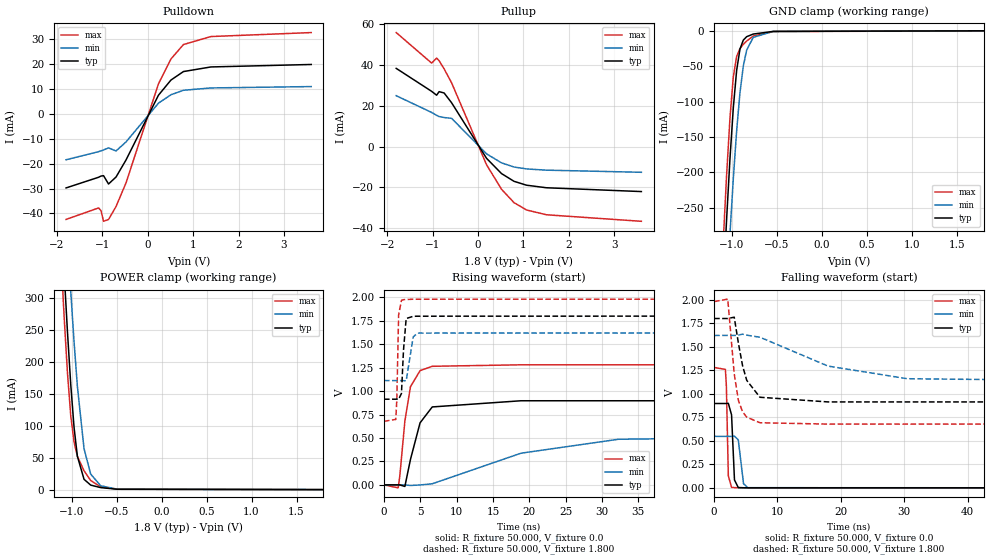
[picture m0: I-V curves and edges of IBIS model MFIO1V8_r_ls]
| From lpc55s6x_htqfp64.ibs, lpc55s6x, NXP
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|   Model MFIO1V8_r_ls
[Model] MFIO1V8_r_ls
Model_type I/O
Polarity   Non-Inverting
Enable   Active-Low
Vinl =  0.540V
Vinh =  1.260V
Vmeas =  0.900V
Cref =  0.0F
Rref =  100.000
Vref =  0.0V
C_comp   2.019pF   1.989pF   2.027pF
C_comp_pullup   1.198pF   1.161pF   1.230pF
C_comp_pulldown   0.670pF   0.640pF   0.684pF
[Model Spec]
Vinh   1.260V   1.134V   1.386V
Vinl   0.540V   0.486V   0.594V
Vmeas   0.900V   0.810V   0.990V
Vref   0.0V   0.0V   0.0V
Cref   0.0F   0.0F   0.0F
Rref   100.000   100.000   100.000
[Temperature Range]   25.000   0.125k   -40.000
[Voltage Range]   1.800V   1.620V   1.980V
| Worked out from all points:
|   slope of the pulldown table from 0 to 0.27 V, typ, clamps not added: 32.2 ohm
|   slope of the pullup table from 0 to 0.27 V, typ, clamps not added: 34.3 ohm
|   GND clamp passes 1 mA (typ) near -0.56 V on its own axis
|   POWER clamp passes 1 mA (typ) near -0.54 V on its own axis
|   rising waveform, R_fixture 50.000, V_fixture 0.0: 20-80 % time 1.89ns typ, 15.8ns min, 1.22ns max; typ from 0 V to 0.897 V
|   rising waveform, R_fixture 50.000, V_fixture 1.800: 20-80 % time 275ps typ, 401ps min, 192ps max; typ from 0.913 V to 1.8 V
|   falling waveform, R_fixture 50.000, V_fixture 0.0: 20-80 % time 312ps typ, 491ps min, 221ps max; typ from 0.897 V to 0 V
|   falling waveform, R_fixture 50.000, V_fixture 1.800: 20-80 % time 1.84ns typ, 13.6ns min, 1.28ns max; typ from 1.8 V to 0.913 V
[Pulldown]
|Voltage   I(typ)   I(min)   I(max)
-1.8V     -29.75mA   -18.45mA   -42.39mA
-1.085V   -25.48mA   -15.2mA    -37.79mA
-1.03V    -24.99mA   -14.87mA   -38.88mA
-975mV    -24.83mA   -14.51mA   -43.15mA
-865mV    -28.18mA   -13.68mA   -42.43mA
-700mV    -25.38mA   -14.92mA   -37.23mA
-480mV    -18.54mA   -11.29mA   -27.73mA
235mV     7.474mA    4.265mA    12.03mA
510mV     13.55mA    7.648mA    22.01mA
785mV     16.96mA    9.446mA    27.8mA
1.39V     18.81mA    10.38mA    31.01mA
3.6V      19.8mA     10.93mA    32.61mA
[Pullup]
|Voltage   I(typ)   I(min)   I(max)
-1.8V     38.29mA    24.9mA     55.82mA
-1.02V    27.05mA    16.71mA    40.87mA
-910mV    25.14mA    15.31mA    43.32mA
-855mV    26.89mA    14.69mA    42.04mA
-745mV    26.24mA    14.22mA    38.06mA
-580mV    21.45mA    13.82mA    31.22mA
190mV     -5.761mA   -3.564mA   -8.914mA
520mV     -13.24mA   -7.997mA   -20.92mA
795mV     -17.02mA   -10.03mA   -27.47mA
1.07V     -18.92mA   -10.95mA   -31.04mA
1.51V     -20.18mA   -11.56mA   -33.41mA
3.6V      -22.04mA   -12.6mA    -36.6mA
[GND_clamp]
|Voltage   I(typ)   I(min)   I(max)
-1.8V     -2.463A    -2.494A    -2.446A
-1.097V   -357.7mA   -460.7mA   -294.8mA
-1.06V    -264.9mA   -370.9mA   -202.5mA
-1.023V   -180.4mA   -286.3mA   -122.9mA
-986mV    -108.7mA   -208.9mA   -65.05mA
-949mV    -56.06mA   -141.4mA   -36.24mA
-912mV    -25.87mA   -87.65mA   -25.01mA
-875mV    -13.21mA   -49.99mA   -19.06mA
-838mV    -8.315mA   -27.44mA   -14.52mA
-764mV    -4.558mA   -9.219mA   -7.395mA
-542mV    -813.9uA   -810.7uA   -1.086mA
1.8V      0A         0A         -4.189uA
[POWER_clamp]
|Voltage   I(typ)   I(min)   I(max)
-1.8V     2.577A     2.626A     2.553A
-1.123V   442.8mA    582.7mA    371.7mA
-1.086V   342mA      487.8mA    272.2mA
-1.049V   248.2mA    396.7mA    184.1mA
-1.012V   164.7mA    310.5mA    115.9mA
-975mV    97.36mA    231.1mA    74.42mA
-938mV    52.18mA    161.5mA    52.15mA
-864mV    16.11mA    64.03mA    29.39mA
-790mV    7.037mA    24.23mA    14.18mA
-679mV    3.116mA    6.059mA    4.361mA
-494mV    554.4uA    627.7uA    712.3uA
1.8V      0A         0A         4.198uA
[Ramp]
| variable   typ   min   max
dV/dt_r   0.538/1.890n   0.328/15.774n   0.768/1.212n
dV/dt_f   0.532/1.835n   0.305/13.605n   0.781/1.279n
R_load = 50.000
[Rising Waveform]
R_fixture= 50.000
V_fixture= 0.0
V_fixture_min= 0.0
V_fixture_max= 0.0
|time   V(typ)   V(min)   V(max)
0s        6.721nV    117.6nV    4.416nV
1.96ns    159.3uV    57.69nV    -31.68mV
2.19ns    -130.7uV   -10.85uV   100.6mV
2.88ns    -16.7mV    114.5uV    679.8mV
3.65ns    271.3mV    -6.131mV   1.047V
4.97ns    661.3mV    -811.5uV   1.218V
6.65ns    830.9mV    11.83mV    1.264V
18.87ns   896.7mV    337.8mV    1.28V
32.27ns   896.7mV    486.3mV    1.28V
100ns     896.7mV    547.3mV    1.28V
[Rising Waveform]
R_fixture= 50.000
V_fixture= 1.800
V_fixture_min= 1.620
V_fixture_max= 1.980
|time   V(typ)   V(min)   V(max)
0s        913.3mV    1.112V     677.7mV
1.63ns    913.3mV    1.112V     697.8mV
1.77ns    913.5mV    1.112V     906.3mV
2.02ns    911.7mV    1.112V     1.812V
2.41ns    974.9mV    1.112V     1.967V
2.69ns    1.437V     1.111V     1.974V
3.06ns    1.773V     1.109V     1.976V
4.03ns    1.797V     1.578V     1.979V
4.64ns    1.798V     1.618V     1.979V
100ns     1.8V       1.62V      1.98V
[Falling Waveform]
R_fixture= 50.000
V_fixture= 0.0
V_fixture_min= 0.0
V_fixture_max= 0.0
|time   V(typ)   V(min)   V(max)
0s        896.7mV    547.4mV    1.28V
1.79ns    896.7mV    547.4mV    1.259V
1.94ns    896.6mV    547.4mV    1.083V
2.25ns    898.7mV    547.4mV    128mV
2.76ns    775.2mV    547.3mV    5.302mV
3.22ns    84.03mV    549.9mV    2.398mV
3.82ns    3.468mV    510.2mV    772.7uV
4.65ns    1.171mV    43.86mV    347.1uV
5.32ns    657.5uV    1.784mV    189.2uV
100ns     14.3nV     184.2nV    8.878nV
[Falling Waveform]
R_fixture= 50.000
V_fixture= 1.800
V_fixture_min= 1.620
V_fixture_max= 1.980
|time   V(typ)   V(min)   V(max)
0s        1.8V       1.62V      1.98V
2.16ns    1.8V       1.62V      2.006V
3.18ns    1.814V     1.62V      1.212V
3.84ns    1.538V     1.623V     928.3mV
4.5ns     1.297V     1.634V     808mV
5.16ns    1.142V     1.623V     751.1mV
7.24ns    962.9mV    1.601V     692.1mV
18ns      913.4mV    1.294V     677.7mV
30.5ns    913.3mV    1.16V      677.7mV
100ns     913.3mV    1.112V     677.7mV
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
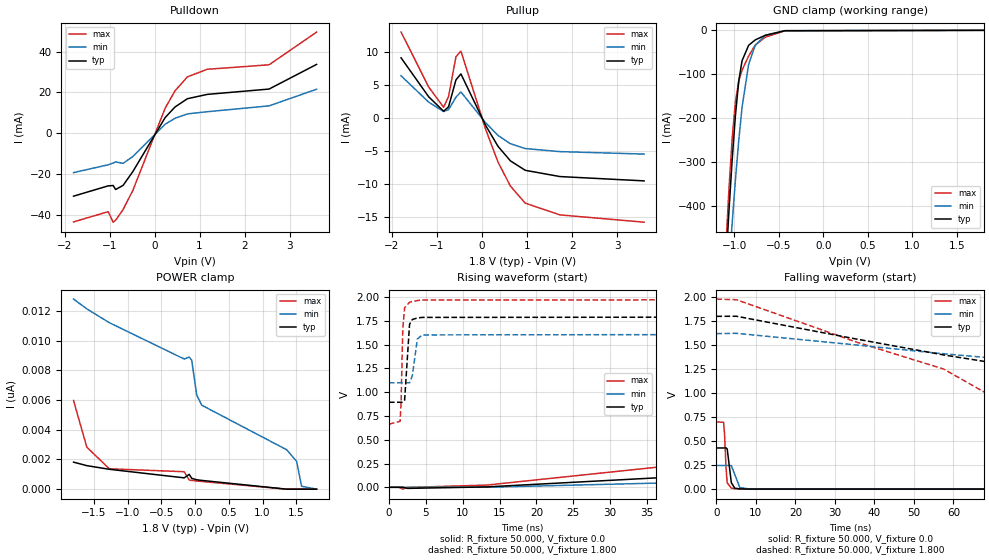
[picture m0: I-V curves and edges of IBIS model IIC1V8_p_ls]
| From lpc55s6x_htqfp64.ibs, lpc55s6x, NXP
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|   Model IIC1V8_p_ls
[Model] IIC1V8_p_ls
Model_type I/O
Polarity   Non-Inverting
Enable   Active-Low
Vinl =  0.540V
Vinh =  1.260V
Vmeas =  0.900V
Cref =  0.0F
Rref =  100.000
Vref =  0.0V
C_comp   2.458pF   2.407pF   2.512pF
C_comp_pullup   0.439pF   0.382pF   0.517pF
C_comp_pulldown   1.692pF   1.593pF   1.772pF
[Model Spec]
Vinh   1.260V   1.134V   1.386V
Vinl   0.540V   0.486V   0.594V
Vmeas   0.900V   0.810V   0.990V
Vref   0.0V   0.0V   0.0V
Cref   0.0F   0.0F   0.0F
Rref   1000.000   1000.000   1000.000
[Temperature Range]   25.000   0.125k   -40.000
[Voltage Range]   1.800V   1.620V   1.980V
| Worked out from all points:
|   slope of the pulldown table from 0 to 0.27 V, typ, clamps not added: 31.5 ohm
|   slope of the pullup table from 0 to 0.27 V, typ, clamps not added: 79.6 ohm
|   GND clamp passes 1 mA (typ) near -0.44 V on its own axis
|   rising waveform, R_fixture 50.000, V_fixture 0.0: 20-80 % time 70.4ns typ, 79.7ns min, 57.9ns max; typ from 0 V to 0.424 V
|   rising waveform, R_fixture 50.000, V_fixture 1.800: 20-80 % time 331ps typ, 508ps min, 248ps max; typ from 0.894 V to 1.8 V
|   falling waveform, R_fixture 50.000, V_fixture 0.0: 20-80 % time 692ps typ, 1.08ns min, 491ps max; typ from 0.429 V to 0 V
|   falling waveform, R_fixture 50.000, V_fixture 1.800: 20-80 % time 66.4ns typ, 87.3ns min, 48.6ns max; typ from 1.8 V to 0.898 V
[Pulldown]
|Voltage   I(typ)   I(min)   I(max)
-1.8V     -30.97mA   -19.41mA   -43.61mA
-1.03V    -25.91mA   -15.56mA   -38.59mA
-920mV    -25.75mA   -14.67mA   -43.75mA
-865mV    -27.69mA   -14.16mA   -42.79mA
-700mV    -25.69mA   -14.87mA   -37.58mA
-480mV    -18.8mA    -11.48mA   -28.03mA
235mV     7.618mA    4.356mA    12.23mA
455mV     12.83mA    7.267mA    20.76mA
730mV     16.88mA    9.427mA    27.6mA
1.17V     19mA       10.49mA    31.33mA
2.545V    21.62mA    13.37mA    33.53mA
3.6V      33.73mA    21.54mA    49.59mA
[Pullup]
|Voltage   I(typ)   I(min)   I(max)
-1.8V     9.182mA    6.453mA    13.09mA
-1.185V   3.25mA     2.442mA    4.736mA
-855mV    1.068mA    1.021mA    1.667mA
-745mV    1.738mA    1.301mA    3.295mA
-580mV    5.828mA    3.21mA     9.347mA
-470mV    6.736mA    3.995mA    10.2mA
80mV      -1.101mA   -685.2uA   -1.694mA
355mV     -4.27mA    -2.612mA   -6.67mA
630mV     -6.475mA   -3.874mA   -10.31mA
960mV     -7.909mA   -4.605mA   -12.9mA
1.73V     -8.857mA   -5.07mA    -14.68mA
3.6V      -9.515mA   -5.442mA   -15.79mA
[GND_clamp]
|Voltage   I(typ)   I(min)   I(max)
-1.8V     -3.488A    -3.23A     -3.872A
-1.097V   -545.5mA   -658.5mA   -507mA
-1.06V    -414.6mA   -546.1mA   -365mA
-1.023V   -294.9mA   -439.1mA   -245.9mA
-986mV    -192.4mA   -339.5mA   -162mA
-949mV    -115.6mA   -250.3mA   -115.1mA
-912mV    -69.18mA   -175.2mA   -90.61mA
-838mV    -34.01mA   -77.15mA   -58.49mA
-764mV    -21.81mA   -34.1mA    -33.59mA
-653mV    -11.42mA   -11.64mA   -15.82mA
-431mV    -827.9uA   -873.5uA   -1.132mA
1.8V      0A         0A         0A
[POWER_clamp]
|Voltage   I(typ)   I(min)   I(max)
-1.8V     1.82nA     12.81nA    5.971nA
-1.604V   1.585nA    12.15nA    2.835nA
-1.271V   1.34nA     11.22nA    1.374nA
-161mV    762.4pA    8.77nA     1.175nA
-87mV     998.4pA    8.9nA      618.7pA
-50mV     731.2pA    8.692nA    590.6pA
24mV      632.5pA    6.343nA    553.1pA
98mV      590.6pA    5.66nA     518.6pA
1.356V    0A         2.658nA    0A
1.504V    0A         1.877nA    0A
1.578V    0A         193.2pA    0A
1.8V      0A         0A         0A
[Ramp]
| variable   typ   min   max
dV/dt_r   0.254/70.441n   0.143/79.670n   0.418/57.882n
dV/dt_f   0.541/66.425n   0.309/87.284n   0.789/48.649n
R_load = 50.000
[Rising Waveform]
R_fixture= 50.000
V_fixture= 0.0
V_fixture_min= 0.0
V_fixture_max= 0.0
|time   V(typ)   V(min)   V(max)
0s        7.216nV    72.68nV    5.103nV
1.38ns    40.03nV    72.67nV    -53.97uV
1.89ns    158.8uV    -182.4nV   -19.68mV
2.54ns    -11.52mV   122.8uV    -1.662mV
13.28ns   4.204mV    620.7uV    23.5mV
52.72ns   167.1mV    75.27mV    344.9mV
82.72ns   273.8mV    136.1mV    543.2mV
96.92ns   316.3mV    159.1mV    608.2mV
136.4ns   395mV      208.3mV    678.4mV
200ns     424mV      239mV      697.4mV
[Rising Waveform]
R_fixture= 50.000
V_fixture= 1.800
V_fixture_min= 1.620
V_fixture_max= 1.980
|time   V(typ)   V(min)   V(max)
0s        894.5mV    1.099V     663.4mV
1.52ns    894.4mV    1.099V     693.6mV
1.65ns    894.5mV    1.099V     889.2mV
1.88ns    893.8mV    1.099V     1.666V
2.13ns    915.7mV    1.099V     1.887V
2.8ns     1.715V     1.099V     1.946V
3.17ns    1.765V     1.172V     1.955V
3.86ns    1.781V     1.56V      1.964V
4.53ns    1.787V     1.603V     1.97V
200ns     1.8V       1.62V      1.98V
[Falling Waveform]
R_fixture= 50.000
V_fixture= 0.0
V_fixture_min= 0.0
V_fixture_max= 0.0
|time   V(typ)   V(min)   V(max)
0s        429.1mV    246.5mV    699.9mV
1.82ns    429.1mV    246.5mV    696.1mV
2.06ns    429mV      246.5mV    576.2mV
2.46ns    430mV      246.5mV    207.8mV
2.74ns    417.7mV    246.5mV    65.71mV
3.78ns    67.3mV     245.2mV    10.27mV
4.66ns    9.798mV    151.3mV    4.768mV
5.93ns    3.017mV    16.56mV    2.397mV
8.46ns    963.1uV    1.41mV     1.239mV
200ns     205.9nV    471.9nV    110nV
[Falling Waveform]
R_fixture= 50.000
V_fixture= 1.800
V_fixture_min= 1.620
V_fixture_max= 1.980
|time   V(typ)   V(min)   V(max)
0s        1.8V       1.62V      1.98V
5.08ns    1.801V     1.623V     1.973V
35.38ns   1.564V     1.502V     1.533V
57.54ns   1.398V     1.41V      1.251V
71.59ns   1.306V     1.36V      922.7mV
85ns      1.187V     1.317V     776.5mV
100.4ns   1.037V     1.271V     712.2mV
120.6ns   953.2mV    1.204V     681.5mV
151.2ns   912mV      1.133V     668.1mV
200ns     898mV      1.106V     664.3mV
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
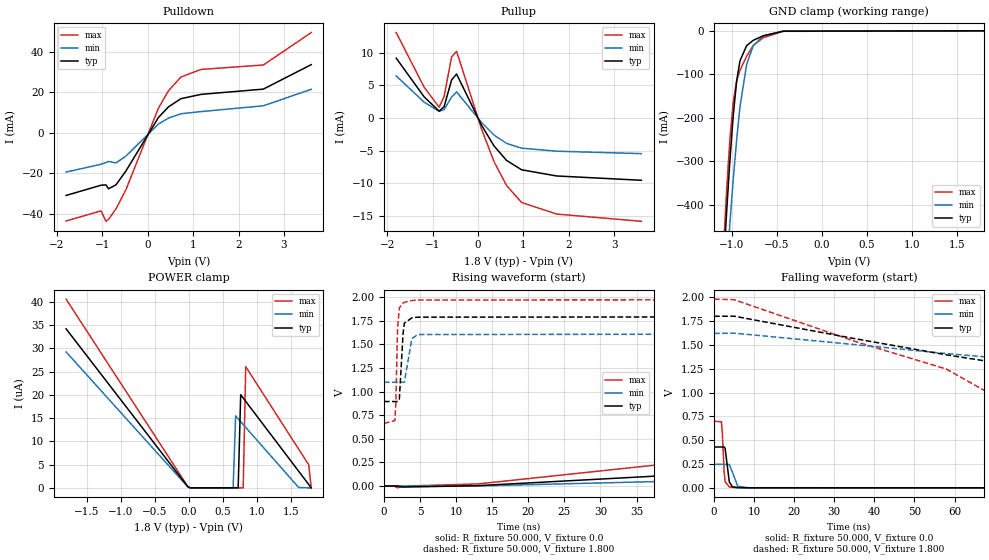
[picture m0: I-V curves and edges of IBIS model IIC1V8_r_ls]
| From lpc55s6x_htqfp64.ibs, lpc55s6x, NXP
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|   Model IIC1V8_r_ls
[Model] IIC1V8_r_ls
Model_type I/O
Polarity   Non-Inverting
Enable   Active-Low
Vinl =  0.540V
Vinh =  1.260V
Vmeas =  0.900V
Cref =  0.0F
Rref =  100.000
Vref =  0.0V
C_comp   2.458pF   2.407pF   2.512pF
C_comp_pullup   0.438pF   0.382pF   0.516pF
C_comp_pulldown   1.694pF   1.594pF   1.774pF
[Model Spec]
Vinh   1.260V   1.134V   1.386V
Vinl   0.540V   0.486V   0.594V
Vmeas   0.900V   0.810V   0.990V
Vref   0.0V   0.0V   0.0V
Cref   0.0F   0.0F   0.0F
Rref   1000.000   1000.000   1000.000
[Temperature Range]   25.000   0.125k   -40.000
[Voltage Range]   1.800V   1.620V   1.980V
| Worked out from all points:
|   slope of the pulldown table from 0 to 0.27 V, typ, clamps not added: 31.5 ohm
|   slope of the pullup table from 0 to 0.27 V, typ, clamps not added: 79.6 ohm
|   GND clamp passes 1 mA (typ) near -0.44 V on its own axis
|   rising waveform, R_fixture 50.000, V_fixture 0.0: 20-80 % time 70.4ns typ, 79.7ns min, 57.9ns max; typ from 0 V to 0.424 V
|   rising waveform, R_fixture 50.000, V_fixture 1.800: 20-80 % time 332ps typ, 505ps min, 248ps max; typ from 0.895 V to 1.8 V
|   falling waveform, R_fixture 50.000, V_fixture 0.0: 20-80 % time 694ps typ, 1.08ns min, 483ps max; typ from 0.429 V to 0 V
|   falling waveform, R_fixture 50.000, V_fixture 1.800: 20-80 % time 66.4ns typ, 87.3ns min, 48.7ns max; typ from 1.8 V to 0.899 V
[Pulldown]
|Voltage   I(typ)   I(min)   I(max)
-1.8V     -30.97mA   -19.41mA   -43.61mA
-1.03V    -25.91mA   -15.56mA   -38.59mA
-920mV    -25.75mA   -14.67mA   -43.75mA
-865mV    -27.69mA   -14.16mA   -42.79mA
-700mV    -25.69mA   -14.87mA   -37.58mA
-480mV    -18.8mA    -11.48mA   -28.03mA
235mV     7.618mA    4.356mA    12.23mA
455mV     12.83mA    7.267mA    20.76mA
730mV     16.88mA    9.427mA    27.6mA
1.17V     19mA       10.49mA    31.33mA
2.545V    21.61mA    13.36mA    33.53mA
3.6V      33.71mA    21.52mA    49.57mA
[Pullup]
|Voltage   I(typ)   I(min)   I(max)
-1.8V     9.162mA    6.436mA    13.07mA
-1.185V   3.238mA    2.432mA    4.723mA
-855mV    1.061mA    1.015mA    1.659mA
-745mV    1.732mA    1.297mA    3.288mA
-580mV    5.824mA    3.207mA    9.344mA
-470mV    6.735mA    3.993mA    10.2mA
80mV      -1.101mA   -685.2uA   -1.694mA
355mV     -4.27mA    -2.612mA   -6.67mA
630mV     -6.475mA   -3.874mA   -10.31mA
960mV     -7.909mA   -4.605mA   -12.9mA
1.73V     -8.857mA   -5.07mA    -14.68mA
3.6V      -9.515mA   -5.442mA   -15.79mA
[GND_clamp]
|Voltage   I(typ)   I(min)   I(max)
-1.8V     -3.488A    -3.23A     -3.872A
-1.097V   -545.5mA   -658.5mA   -507mA
-1.06V    -414.6mA   -546.1mA   -365mA
-1.023V   -294.9mA   -439.1mA   -245.9mA
-986mV    -192.4mA   -339.6mA   -162mA
-949mV    -115.6mA   -250.3mA   -115.1mA
-912mV    -69.19mA   -175.2mA   -90.62mA
-838mV    -34.02mA   -77.16mA   -58.5mA
-764mV    -21.82mA   -34.11mA   -33.6mA
-653mV    -11.43mA   -11.65mA   -15.83mA
-431mV    -835.3uA   -879.6uA   -1.141mA
1.8V      0A         0A         0A
[POWER_clamp]
|Voltage   I(typ)   I(min)   I(max)
-1.8V     34.22uA    29.25uA    40.61uA
-13mV     251.2nA    223.3nA    296.4nA
24mV      0A         0A         0A
653mV     0A         0A         0A
690mV     0A         15.47uA    0A
727mV     0A         14.85uA    0A
764mV     20.04uA    14.24uA    0A
801mV     19.32uA    13.62uA    0A
838mV     18.61uA    13.01uA    26.08uA
1.615V    3.579uA    80.87nA    8.337uA
1.763V    715.6nA    0A         4.957uA
1.8V      0A         0A         0A
[Ramp]
| variable   typ   min   max
dV/dt_r   0.254/70.445n   0.143/79.671n   0.418/57.889n
dV/dt_f   0.541/66.452n   0.308/87.295n   0.790/48.705n
R_load = 50.000
[Rising Waveform]
R_fixture= 50.000
V_fixture= 0.0
V_fixture_min= 0.0
V_fixture_max= 0.0
|time   V(typ)   V(min)   V(max)
0s        6.589nV    69.96nV    4.613nV
1.38ns    39.38nV    69.96nV    -52.13uV
1.89ns    158.7uV    -194.9nV   -19.68mV
2.54ns    -11.49mV   121.5uV    -1.662mV
13.06ns   3.769mV    530.2uV    22.13mV
52.67ns   166.7mV    75.11mV    344.2mV
82.67ns   273.4mV    135.9mV    542.4mV
96.87ns   315.9mV    158.9mV    607.4mV
136.4ns   394.6mV    208.1mV    677.7mV
200ns     423.7mV    238.8mV    696.7mV
[Rising Waveform]
R_fixture= 50.000
V_fixture= 1.800
V_fixture_min= 1.620
V_fixture_max= 1.980
|time   V(typ)   V(min)   V(max)
0s        895.1mV    1.1V       663mV
1.52ns    895.1mV    1.1V       693.4mV
1.65ns    895.2mV    1.1V       888.8mV
1.88ns    894.5mV    1.1V       1.666V
2.13ns    916.4mV    1.1V       1.887V
2.65ns    1.616V     1.099V     1.94V
2.83ns    1.726V     1.1V       1.946V
3.86ns    1.781V     1.56V      1.965V
4.67ns    1.789V     1.605V     1.971V
200ns     1.8V       1.62V      1.98V
[Falling Waveform]
R_fixture= 50.000
V_fixture= 0.0
V_fixture_min= 0.0
V_fixture_max= 0.0
|time   V(typ)   V(min)   V(max)
0s        428.7mV    246.3mV    699.2mV
1.84ns    428.7mV    246.3mV    692.6mV
2.06ns    428.6mV    246.3mV    575.2mV
2.51ns    429.7mV    246.3mV    171.5mV
2.75ns    416.1mV    246.3mV    63.5mV
3.8ns     62.56mV    244.7mV    9.47mV
4.6ns     10.16mV    161.4mV    4.498mV
5.9ns     2.796mV    17.6mV     2.083mV
8.41ns    821.5uV    1.323mV    1.072mV
200ns     205.2nV    468.9nV    109.5nV
[Falling Waveform]
R_fixture= 50.000
V_fixture= 1.800
V_fixture_min= 1.620
V_fixture_max= 1.980
|time   V(typ)   V(min)   V(max)
0s        1.8V       1.62V      1.98V
5.02ns    1.801V     1.623V     1.974V
35.41ns   1.563V     1.502V     1.533V
57.9ns    1.396V     1.409V     1.247V
71.61ns   1.306V     1.36V      923.4mV
85.57ns   1.181V     1.316V     772.5mV
100.5ns   1.038V     1.271V     711.8mV
120.7ns   953.8mV    1.204V     681.1mV
151.3ns   912.7mV    1.133V     667.7mV
200ns     898.6mV    1.106V     663.9mV
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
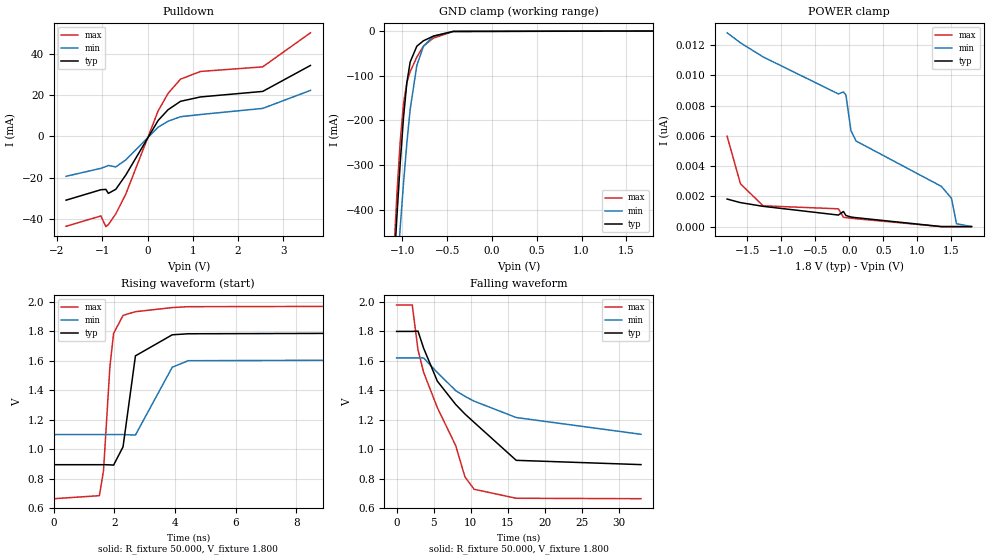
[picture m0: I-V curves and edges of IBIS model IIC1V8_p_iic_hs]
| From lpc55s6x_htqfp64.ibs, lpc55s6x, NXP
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|   Model IIC1V8_p_iic_hs
[Model] IIC1V8_p_iic_hs
Model_type I/O_open_drain
Polarity   Non-Inverting
Enable   Active-Low
Vinl =  0.540V
Vinh =  1.260V
Vmeas =  0.900V
Cref =  0.0F
Rref =  100.000
Vref =  1.800V
C_comp   2.439pF   2.391pF   2.494pF
C_comp_pulldown   1.723pF   1.659pF   1.780pF
C_comp_power_clamp   0.386pF   0.354pF   0.434pF
[Model Spec]
Vinh   1.260V   1.134V   1.386V
Vinl   0.540V   0.486V   0.594V
Vmeas   0.900V   0.810V   0.990V
Vref   1.800V   1.620V   1.980V
Cref   0.0F   0.0F   0.0F
Rref   100.000   100.000   100.000
[Temperature Range]   25.000   0.125k   -40.000
[Voltage Range]   1.800V   1.620V   1.980V
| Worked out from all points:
|   slope of the pulldown table from 0 to 0.27 V, typ, clamps not added: 31.5 ohm
|   GND clamp passes 1 mA (typ) near -0.44 V on its own axis
|   rising waveform, R_fixture 50.000, V_fixture 1.800: 20-80 % time 347ps typ, 537ps min, 254ps max; typ from 0.894 V to 1.8 V
|   falling waveform, R_fixture 50.000, V_fixture 1.800: 20-80 % time 8.41ns typ, 11.3ns min, 5.73ns max; typ from 1.8 V to 0.895 V
[Pulldown]
|Voltage   I(typ)   I(min)   I(max)
-1.8V     -30.97mA   -19.41mA   -43.61mA
-1.03V    -25.91mA   -15.56mA   -38.59mA
-920mV    -25.75mA   -14.67mA   -43.75mA
-865mV    -27.69mA   -14.16mA   -42.79mA
-700mV    -25.69mA   -14.87mA   -37.58mA
-480mV    -18.8mA    -11.48mA   -28.03mA
235mV     7.619mA    4.356mA    12.23mA
455mV     12.83mA    7.267mA    20.76mA
730mV     16.88mA    9.427mA    27.6mA
1.17V     19mA       10.49mA    31.33mA
2.545V    21.67mA    13.45mA    33.55mA
3.6V      34.24mA    22.16mA    50.03mA
[GND_clamp]
|Voltage   I(typ)   I(min)   I(max)
-1.8V     -3.488A    -3.23A     -3.872A
-1.097V   -545.5mA   -658.5mA   -507mA
-1.06V    -414.6mA   -546.1mA   -365mA
-1.023V   -294.9mA   -439.1mA   -245.9mA
-986mV    -192.4mA   -339.5mA   -162mA
-949mV    -115.6mA   -250.3mA   -115.1mA
-912mV    -69.18mA   -175.2mA   -90.61mA
-838mV    -34.01mA   -77.15mA   -58.49mA
-764mV    -21.81mA   -34.1mA    -33.59mA
-653mV    -11.42mA   -11.64mA   -15.82mA
-431mV    -827.9uA   -873.5uA   -1.132mA
1.8V      0A         0A         0A
[POWER_clamp]
|Voltage   I(typ)   I(min)   I(max)
-1.8V     1.82nA     12.81nA    5.971nA
-1.604V   1.585nA    12.15nA    2.835nA
-1.271V   1.34nA     11.22nA    1.374nA
-161mV    762.4pA    8.77nA     1.175nA
-87mV     998.4pA    8.9nA      618.7pA
-50mV     731.2pA    8.692nA    590.6pA
24mV      632.5pA    6.343nA    553.1pA
98mV      590.6pA    5.66nA     518.6pA
1.356V    0A         2.658nA    0A
1.504V    0A         1.877nA    0A
1.578V    0A         193.2pA    0A
1.8V      0A         0A         0A
[Ramp]
| variable   typ   min   max
dV/dt_r   0.543/0.347n   0.312/0.537n   0.790/0.254n
dV/dt_f   0.543/8.409n   0.311/11.269n   0.790/5.726n
R_load = 50.000
[Rising Waveform]
R_fixture= 50.000
V_fixture= 1.800
V_fixture_min= 1.620
V_fixture_max= 1.980
|time   V(typ)   V(min)   V(max)
0s        894.4mV    1.099V     663.4mV
1.504ns   894.4mV    1.099V     683.9mV
1.64ns    894.6mV    1.099V     853.3mV
1.851ns   893.3mV    1.099V     1.56V
1.973ns   891.6mV    1.099V     1.786V
2.285ns   1.016V     1.099V     1.909V
2.694ns   1.634V     1.096V     1.934V
3.909ns   1.777V     1.557V     1.962V
4.437ns   1.784V     1.601V     1.968V
33ns      1.8V       1.62V      1.98V
[Falling Waveform]
R_fixture= 50.000
V_fixture= 1.800
V_fixture_min= 1.620
V_fixture_max= 1.980
|time   V(typ)   V(min)   V(max)
0s        1.8V       1.62V      1.98V
2.115ns   1.8V       1.62V      1.98V
2.892ns   1.802V     1.62V      1.674V
3.642ns   1.687V     1.62V      1.523V
5.504ns   1.462V     1.521V     1.282V
7.976ns   1.304V     1.398V     1.025V
9.227ns   1.239V     1.359V     812.1mV
10.47ns   1.182V     1.326V     727.5mV
16.15ns   924.2mV    1.215V     666.4mV
33ns      895mV      1.101V     663.5mV
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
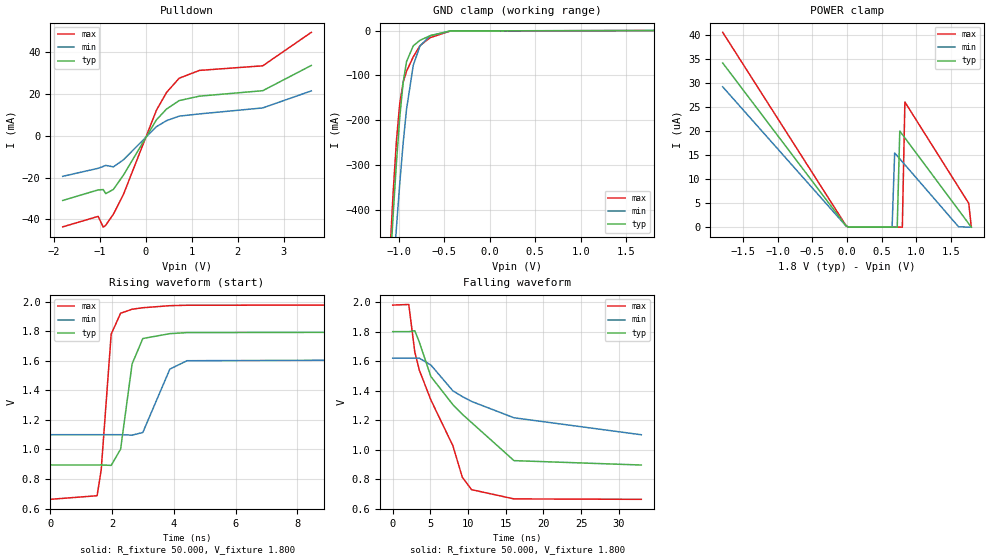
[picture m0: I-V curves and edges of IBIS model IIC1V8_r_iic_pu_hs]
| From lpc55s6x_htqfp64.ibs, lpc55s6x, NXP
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|   Model IIC1V8_r_iic_pu_hs
[Model] IIC1V8_r_iic_pu_hs
Model_type I/O_open_drain
Polarity   Non-Inverting
Enable   Active-Low
Vinl =  0.540V
Vinh =  1.260V
Vmeas =  0.900V
Cref =  0.0F
Rref =  100.000
Vref =  1.8V
C_comp   2.515pF   2.512pF   2.535pF
C_comp_pulldown   1.736pF   1.670pF   1.792pF
C_comp_power_clamp   0.454pF   0.388pF   0.547pF
[Model Spec]
Vinh   1.260V   1.134V   1.386V
Vinl   0.540V   0.486V   0.594V
Vmeas   0.900V   0.810V   0.990V
Vref   1.800V   1.620V   1.980V
Cref   0.0F   0.0F   0.0F
Rref   100.000   100.000   100.000
[Temperature Range]   25.000   0.125k   -40.000
[Voltage Range]   1.800V   1.620V   1.980V
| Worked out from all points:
|   slope of the pulldown table from 0 to 0.27 V, typ, clamps not added: 31.5 ohm
|   GND clamp passes 1 mA (typ) near -0.44 V on its own axis
|   rising waveform, R_fixture 50.000, V_fixture 1.800: 20-80 % time 347ps typ, 536ps min, 254ps max; typ from 0.895 V to 1.8 V
|   falling waveform, R_fixture 50.000, V_fixture 1.800: 20-80 % time 8.38ns typ, 11.2ns min, 5.72ns max; typ from 1.8 V to 0.896 V
[Pulldown]
|Voltage   I(typ)   I(min)   I(max)
-1.8V     -30.97mA   -19.41mA   -43.61mA
-1.03V    -25.91mA   -15.56mA   -38.59mA
-920mV    -25.75mA   -14.67mA   -43.75mA
-865mV    -27.69mA   -14.16mA   -42.79mA
-700mV    -25.69mA   -14.87mA   -37.58mA
-480mV    -18.8mA    -11.48mA   -28.03mA
235mV     7.619mA    4.356mA    12.23mA
455mV     12.83mA    7.267mA    20.76mA
730mV     16.88mA    9.427mA    27.6mA
1.17V     19mA       10.49mA    31.33mA
2.545V    21.61mA    13.36mA    33.53mA
3.6V      33.71mA    21.52mA    49.57mA
[GND_clamp]
|Voltage   I(typ)   I(min)   I(max)
-1.8V     -3.488A    -3.23A     -3.872A
-1.097V   -545.5mA   -658.5mA   -507mA
-1.06V    -414.6mA   -546.1mA   -365mA
-1.023V   -294.9mA   -439.1mA   -245.9mA
-986mV    -192.4mA   -339.6mA   -162mA
-949mV    -115.6mA   -250.3mA   -115.1mA
-912mV    -69.19mA   -175.2mA   -90.62mA
-838mV    -34.02mA   -77.16mA   -58.5mA
-764mV    -21.82mA   -34.11mA   -33.6mA
-653mV    -11.43mA   -11.65mA   -15.83mA
-431mV    -835.3uA   -879.6uA   -1.141mA
1.8V      0A         0A         0A
[POWER_clamp]
|Voltage   I(typ)   I(min)   I(max)
-1.8V     34.22uA    29.25uA    40.61uA
-13mV     251.2nA    223.3nA    296.4nA
24mV      0A         0A         0A
653mV     0A         0A         0A
690mV     0A         15.47uA    0A
727mV     0A         14.85uA    0A
764mV     20.04uA    14.24uA    0A
801mV     19.32uA    13.62uA    0A
838mV     18.61uA    13.01uA    26.08uA
1.615V    3.579uA    80.87nA    8.337uA
1.763V    715.6nA    0A         4.957uA
1.8V      0A         0A         0A
[Ramp]
| variable   typ   min   max
dV/dt_r   0.543/0.347n   0.312/0.537n   0.790/0.255n
dV/dt_f   0.543/8.379n   0.311/11.175n   0.790/5.718n
R_load = 50.000
[Rising Waveform]
R_fixture= 50.000
V_fixture= 1.800
V_fixture_min= 1.620
V_fixture_max= 1.980
|time   V(typ)   V(min)   V(max)
0s        895.1mV    1.1V       663mV
1.516ns   895.1mV    1.1V       687.5mV
1.648ns   895.3mV    1.1V       860.8mV
1.972ns   892.5mV    1.1V       1.78V
2.277ns   1.002V     1.1V       1.921V
2.649ns   1.578V     1.097V     1.948V
2.996ns   1.75V      1.115V     1.958V
3.871ns   1.783V     1.543V     1.972V
4.427ns   1.79V      1.6V       1.975V
33ns      1.8V       1.62V      1.98V
[Falling Waveform]
R_fixture= 50.000
V_fixture= 1.800
V_fixture_min= 1.620
V_fixture_max= 1.980
|time   V(typ)   V(min)   V(max)
0s        1.8V       1.62V      1.98V
2.133ns   1.8V       1.62V      1.984V
2.927ns   1.806V     1.62V      1.664V
3.534ns   1.729V     1.62V      1.539V
5.064ns   1.496V     1.574V     1.337V
7.983ns   1.305V     1.399V     1.027V
9.238ns   1.24V      1.36V      813.4mV
10.46ns   1.184V     1.327V     728.9mV
16.1ns    925.6mV    1.216V     666.1mV
33ns      895.7mV    1.101V     663.2mV
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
